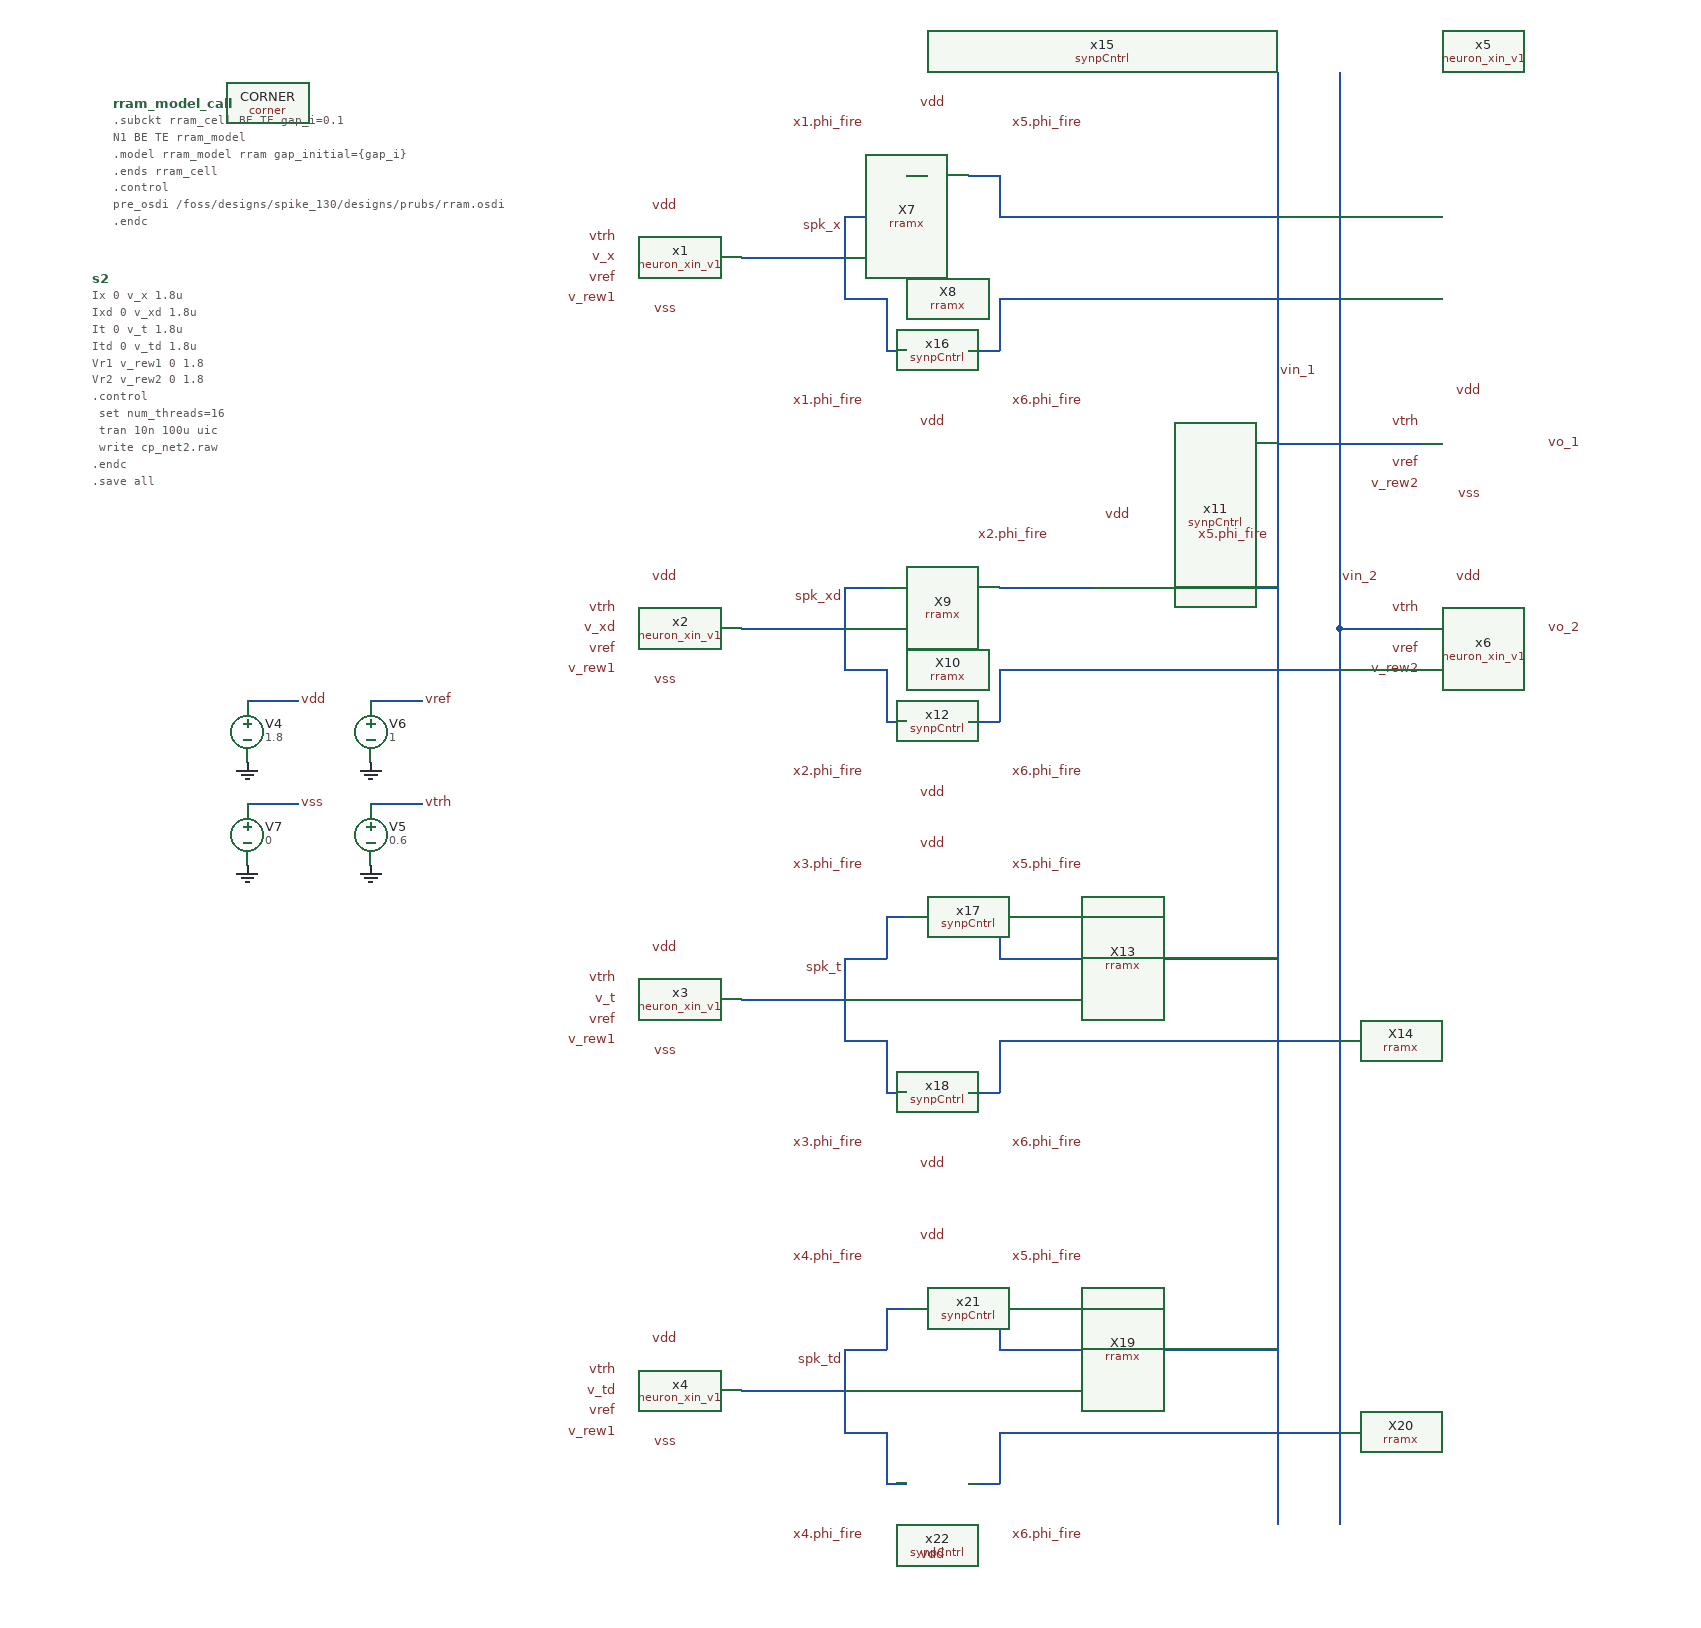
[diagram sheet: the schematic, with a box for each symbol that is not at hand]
v {xschem version=3.4.7 file_version=1.2}
G {}
K {}
V {}
S {}
E {}
B 2 540 -1630 1340 -1230 {flags=graph
y1=0.804
y2=1.924
ypos1=0
ypos2=2
divy=5
subdivy=1
unity=1
x1=-1.4999885e-05
x2=8.5000015e-05
divx=5
subdivx=1
xlabmag=1.0
ylabmag=1.0
node="v_x
v_xd
v_t
v_td"
color="4 13 6 12"
dataset=-1
unitx=1
logx=0
logy=0
}
B 2 1640 -850 2440 -450 {flags=graph
y1=0.63
y2=1.7
ypos1=0
ypos2=2
divy=5
subdivy=1
unity=1
x1=-1.4999885e-05
x2=8.5000015e-05
divx=5
subdivx=1
xlabmag=1.0
ylabmag=1.0
dataset=-1
unitx=1
logx=0
logy=0
color=6
node=spk_t}
B 2 1640 -450 2440 -50 {flags=graph
y1=0.63
y2=1.7
ypos1=0
ypos2=2
divy=5
subdivy=1
unity=1
x1=-1.4999885e-05
x2=8.5000015e-05
divx=5
subdivx=1
xlabmag=1.0
ylabmag=1.0
dataset=-1
unitx=1
logx=0
logy=0
color=12
node=spk_td}
B 2 1640 -1650 2440 -1250 {flags=graph
y1=0.63
y2=1.7
ypos1=0
ypos2=2
divy=5
subdivy=1
unity=1
x1=-1.4999885e-05
x2=8.5000015e-05
divx=5
subdivx=1
xlabmag=1.0
ylabmag=1.0
dataset=-1
unitx=1
logx=0
logy=0
color=4
node=spk_x}
B 2 1640 -1250 2440 -850 {flags=graph
y1=0.61
y2=1.7
ypos1=0
ypos2=2
divy=5
subdivy=1
unity=1
x1=-1.4999885e-05
x2=8.5000015e-05
divx=5
subdivx=1
xlabmag=1.0
ylabmag=1.0
dataset=-1
unitx=1
logx=0
logy=0
color=13
node=spk_xd}
B 2 2550 -1680 3350 -1280 {flags=graph
y1=0.68
y2=1.7
ypos1=0
ypos2=2
divy=5
subdivy=1
unity=1
x1=-1.4999885e-05
x2=8.5000015e-05
divx=5
subdivx=1
xlabmag=1.0
ylabmag=1.0
dataset=-1
unitx=1
logx=0
logy=0
color=5
node=vin_1}
B 2 2550 -1280 3350 -880 {flags=graph
y1=0.68
y2=1.7
ypos1=0
ypos2=2
divy=5
subdivy=1
unity=1
x1=-1.4999885e-05
x2=8.5000015e-05
divx=5
subdivx=1
xlabmag=1.0
ylabmag=1.0
dataset=-1
unitx=1
logx=0
logy=0
color=13
node=vin_2}
B 2 2550 -810 3350 -410 {flags=graph
y1=0.51
y2=1.8
ypos1=0
ypos2=2
divy=5
subdivy=1
unity=1
x1=-1.4999885e-05
x2=8.5000015e-05
divx=5
subdivx=1
xlabmag=1.0
ylabmag=1.0
dataset=-1
unitx=1
logx=0
logy=0
color=7
node=vo_1}
B 2 2550 -410 3350 -10 {flags=graph
y1=0.51
y2=1.8
ypos1=0
ypos2=2
divy=5
subdivy=1
unity=1
x1=-1.4999885e-05
x2=8.5000015e-05
divx=5
subdivx=1
xlabmag=1.0
ylabmag=1.0
dataset=-1
unitx=1
logx=0
logy=0
color=8
node=vo_2}
N 270 -480 320 -480 {
lab=vdd}
N 390 -380 440 -380 {
lab=vtrh}
N 390 -480 440 -480 {
lab=vref}
N 270 -380 320 -380 {
lab=vss}
N 1270 -730 1410 -730 {lab=vin_1}
N 1330 -550 1410 -550 {lab=vin_2}
N 750 -910 850 -910 {lab=spk_x}
N 750 -550 850 -550 {lab=spk_xd}
N 750 -190 850 -190 {lab=spk_t}
N 750 190 850 190 {lab=spk_td}
N 850 -950 850 -870 {lab=spk_x}
N 850 -870 890 -870 {lab=spk_x}
N 850 -950 890 -950 {lab=spk_x}
N 850 -590 850 -510 {lab=spk_xd}
N 850 -230 850 -150 {lab=spk_t}
N 850 150 850 230 {lab=spk_td}
N 890 -990 910 -990 {lab=spk_x}
N 890 -990 890 -950 {lab=spk_x}
N 970 -990 1000 -990 {lab=vin_1}
N 1000 -990 1000 -950 {lab=vin_1}
N 890 -820 910 -820 {lab=spk_x}
N 890 -870 890 -820 {lab=spk_x}
N 1000 -870 1000 -820 {lab=vin_2}
N 970 -820 1000 -820 {lab=vin_2}
N 850 -510 890 -510 {lab=spk_xd}
N 850 -590 890 -590 {lab=spk_xd}
N 890 -460 910 -460 {lab=spk_xd}
N 890 -510 890 -460 {lab=spk_xd}
N 1000 -510 1000 -460 {lab=vin_2}
N 970 -460 1000 -460 {lab=vin_2}
N 850 -150 890 -150 {lab=spk_t}
N 850 -230 890 -230 {lab=spk_t}
N 890 -270 910 -270 {lab=spk_t}
N 890 -270 890 -230 {lab=spk_t}
N 970 -270 1000 -270 {lab=vin_1}
N 1000 -270 1000 -230 {lab=vin_1}
N 890 -100 910 -100 {lab=spk_t}
N 890 -150 890 -100 {lab=spk_t}
N 1000 -150 1000 -100 {lab=vin_2}
N 970 -100 1000 -100 {lab=vin_2}
N 850 230 890 230 {lab=spk_td}
N 850 150 890 150 {lab=spk_td}
N 890 110 910 110 {lab=spk_td}
N 890 110 890 150 {lab=spk_td}
N 970 110 1000 110 {lab=vin_1}
N 1000 110 1000 150 {lab=vin_1}
N 890 280 910 280 {lab=spk_td}
N 890 230 890 280 {lab=spk_td}
N 1000 230 1000 280 {lab=vin_2}
N 970 280 1000 280 {lab=vin_2}
N 1270 -1090 1270 320 {lab=vin_1}
N 1330 -1090 1330 -550 {lab=vin_2}
N 1330 -550 1330 320 {lab=vin_2}
N 1000 230 1330 230 {lab=vin_2}
N 1000 150 1270 150 {lab=vin_1}
N 1000 -150 1330 -150 {lab=vin_2}
N 1000 -230 1270 -230 {lab=vin_1}
N 1000 -510 1330 -510 {lab=vin_2}
N 1000 -950 1270 -950 {lab=vin_1}
N 1000 -870 1330 -870 {lab=vin_2}
N 1000 -590 1090 -590 {lab=#net1}
N 1150 -590 1270 -590 {lab=vin_1}
C {devices/code_shown.sym} 120 -890 0 0 {name=s2 only_toplevel=false value="
Ix 0 v_x 1.8u
Ixd 0 v_xd 1.8u
It 0 v_t 1.8u
Itd 0 v_td 1.8u
Vr1 v_rew1 0 1.8
Vr2 v_rew2 0 1.8
.control
 set num_threads=16
 tran 10n 100u uic
 write cp_net2.raw
.endc
.save all
" }
C {devices/vsource.sym} 270 -450 0 0 {name=V4 value=1.8}
C {devices/gnd.sym} 270 -420 0 0 {name=l9 lab=GND}
C {devices/lab_wire.sym} 320 -480 0 1 {name=p61 sig_type=std_logic lab=vdd}
C {devices/vsource.sym} 390 -350 0 0 {name=V5 value=0.6}
C {devices/gnd.sym} 390 -320 0 0 {name=l10 lab=GND}
C {devices/lab_wire.sym} 440 -380 0 1 {name=p63 sig_type=std_logic lab=vtrh}
C {devices/vsource.sym} 390 -450 0 0 {name=V6 value=1}
C {devices/gnd.sym} 390 -420 0 0 {name=l11 lab=GND}
C {devices/lab_wire.sym} 440 -480 0 1 {name=p64 sig_type=std_logic lab=vref}
C {devices/vsource.sym} 270 -350 0 0 {name=V7 value=0}
C {devices/gnd.sym} 270 -320 0 0 {name=l13 lab=GND}
C {devices/lab_wire.sym} 320 -380 0 1 {name=p72 sig_type=std_logic lab=vss}
C {sky130_fd_pr/corner.sym} 290 -1060 0 0 {name=CORNER only_toplevel=true corner=tt}
C {devices/lab_wire.sym} 630 -890 0 0 {name=p2 sig_type=std_logic lab=vref}
C {devices/lab_wire.sym} 690 -960 0 0 {name=p3 sig_type=std_logic lab=vdd}
C {devices/lab_wire.sym} 630 -930 0 0 {name=p10 sig_type=std_logic lab=vtrh}
C {devices/lab_wire.sym} 690 -860 2 1 {name=p11 sig_type=std_logic lab=vss}
C {devices/lab_wire.sym} 630 -870 0 0 {name=p12 sig_type=std_logic lab=v_rew1}
C {/foss/designs/spike_130/designs/core_xin_neuron_v1/neuron_xin_v1.sym} 690 -910 0 0 {name=x1}
C {devices/lab_wire.sym} 630 -530 0 0 {name=p4 sig_type=std_logic lab=vref}
C {devices/lab_wire.sym} 690 -600 0 0 {name=p6 sig_type=std_logic lab=vdd}
C {devices/lab_wire.sym} 630 -570 0 0 {name=p13 sig_type=std_logic lab=vtrh}
C {devices/lab_wire.sym} 690 -500 2 1 {name=p14 sig_type=std_logic lab=vss}
C {devices/lab_wire.sym} 630 -510 0 0 {name=p15 sig_type=std_logic lab=v_rew1}
C {/foss/designs/spike_130/designs/core_xin_neuron_v1/neuron_xin_v1.sym} 690 -550 0 0 {name=x2}
C {devices/lab_wire.sym} 630 -170 0 0 {name=p16 sig_type=std_logic lab=vref}
C {devices/lab_wire.sym} 690 -240 0 0 {name=p17 sig_type=std_logic lab=vdd}
C {devices/lab_wire.sym} 630 -210 0 0 {name=p18 sig_type=std_logic lab=vtrh}
C {devices/lab_wire.sym} 690 -140 2 1 {name=p19 sig_type=std_logic lab=vss}
C {devices/lab_wire.sym} 630 -150 0 0 {name=p20 sig_type=std_logic lab=v_rew1}
C {/foss/designs/spike_130/designs/core_xin_neuron_v1/neuron_xin_v1.sym} 690 -190 0 0 {name=x3}
C {devices/lab_wire.sym} 630 210 0 0 {name=p21 sig_type=std_logic lab=vref}
C {devices/lab_wire.sym} 690 140 0 0 {name=p22 sig_type=std_logic lab=vdd}
C {devices/lab_wire.sym} 630 170 0 0 {name=p23 sig_type=std_logic lab=vtrh}
C {devices/lab_wire.sym} 690 240 2 1 {name=p24 sig_type=std_logic lab=vss}
C {devices/lab_wire.sym} 630 230 0 0 {name=p25 sig_type=std_logic lab=v_rew1}
C {/foss/designs/spike_130/designs/core_xin_neuron_v1/neuron_xin_v1.sym} 690 190 0 0 {name=x4}
C {devices/lab_wire.sym} 1410 -710 0 0 {name=p26 sig_type=std_logic lab=vref}
C {devices/lab_wire.sym} 1470 -780 0 0 {name=p27 sig_type=std_logic lab=vdd}
C {devices/lab_wire.sym} 1410 -750 0 0 {name=p28 sig_type=std_logic lab=vtrh}
C {devices/lab_wire.sym} 1470 -680 2 1 {name=p30 sig_type=std_logic lab=vss}
C {devices/lab_wire.sym} 1410 -690 0 0 {name=p31 sig_type=std_logic lab=v_rew2}
C {/foss/designs/spike_130/designs/core_xin_neuron_v1/neuron_xin_v1.sym} 1470 -730 0 0 {name=x5}
C {devices/lab_wire.sym} 1410 -530 0 0 {name=p32 sig_type=std_logic lab=vref}
C {devices/lab_wire.sym} 1470 -600 0 0 {name=p33 sig_type=std_logic lab=vdd}
C {devices/lab_wire.sym} 1410 -570 0 0 {name=p34 sig_type=std_logic lab=vtrh}
C {devices/lab_wire.sym} 1470 -500 2 1 {name=p35 sig_type=std_logic lab=vss}
C {devices/lab_wire.sym} 1410 -510 0 0 {name=p36 sig_type=std_logic lab=v_rew2}
C {/foss/designs/spike_130/designs/core_xin_neuron_v1/neuron_xin_v1.sym} 1470 -550 0 0 {name=x6}
C {devices/lab_wire.sym} 630 -910 0 0 {name=p1 sig_type=std_logic lab=v_x}
C {devices/lab_wire.sym} 630 -550 0 0 {name=p7 sig_type=std_logic lab=v_xd}
C {devices/lab_wire.sym} 630 -190 0 0 {name=p8 sig_type=std_logic lab=v_t}
C {devices/lab_wire.sym} 630 190 0 0 {name=p9 sig_type=std_logic lab=v_td}
C {devices/lab_wire.sym} 850 -940 0 0 {name=p37 sig_type=std_logic lab=spk_x}
C {devices/lab_wire.sym} 850 -580 0 0 {name=p38 sig_type=std_logic lab=spk_xd}
C {devices/lab_wire.sym} 850 -220 0 0 {name=p39 sig_type=std_logic lab=spk_t}
C {devices/lab_wire.sym} 850 160 0 0 {name=p40 sig_type=std_logic lab=spk_td}
C {devices/lab_wire.sym} 1530 -730 0 1 {name=p41 sig_type=std_logic lab=vo_1}
C {devices/lab_wire.sym} 1530 -550 0 1 {name=p42 sig_type=std_logic lab=vo_2}
C {devices/lab_wire.sym} 1270 -800 0 1 {name=p47 sig_type=std_logic lab=vin_1}
C {devices/lab_wire.sym} 1330 -600 0 1 {name=p48 sig_type=std_logic lab=vin_2}
C {/foss/designs/spike_130/designs/memristors/rram_v1/rramx.sym} 950 -950 0 0 {name=X7
model=rram_cell
spiceprefix=X
gap_i=0.5
}
C {/foss/designs/spike_130/designs/memristors/rram_v1/rramx.sym} 950 -870 0 0 {name=X8
model=rram_cell
spiceprefix=X
gap_i=0.5
}
C {code.sym} 140 -1060 0 0 {name=rram_model_call only_toplevel=false value=".subckt rram_cell BE TE gap_i=0.1
N1 BE TE rram_model
.model rram_model rram gap_initial=\{gap_i\}
.ends rram_cell

.control
pre_osdi /foss/designs/spike_130/designs/prubs/rram.osdi
.endc"}
C {/foss/designs/spike_130/designs/subcells/core_synpCntrl/synpCntrl.sym} 940 -1030 0 0 {name=x15}
C {devices/lab_wire.sym} 870 -1040 0 0 {name=p5 sig_type=std_logic lab=x1.phi_fire}
C {devices/lab_wire.sym} 1010 -1040 0 1 {name=p29 sig_type=std_logic lab=x5.phi_fire}
C {devices/lab_wire.sym} 920 -1060 0 1 {name=p43 sig_type=std_logic lab=vdd}
C {/foss/designs/spike_130/designs/subcells/core_synpCntrl/synpCntrl.sym} 940 -780 2 1 {name=x16}
C {devices/lab_wire.sym} 870 -770 2 1 {name=p44 sig_type=std_logic lab=x1.phi_fire}
C {devices/lab_wire.sym} 1010 -770 2 0 {name=p45 sig_type=std_logic lab=x6.phi_fire}
C {devices/lab_wire.sym} 920 -750 2 0 {name=p46 sig_type=std_logic lab=vdd}
C {/foss/designs/spike_130/designs/memristors/rram_v1/rramx.sym} 950 -590 0 0 {name=X9
model=rram_cell
spiceprefix=X
gap_i=0.5
}
C {/foss/designs/spike_130/designs/memristors/rram_v1/rramx.sym} 950 -510 0 0 {name=X10
model=rram_cell
spiceprefix=X
gap_i=0.5
}
C {/foss/designs/spike_130/designs/subcells/core_synpCntrl/synpCntrl.sym} 1120 -630 0 0 {name=x11}
C {devices/lab_wire.sym} 1050 -640 0 0 {name=p49 sig_type=std_logic lab=x2.phi_fire}
C {devices/lab_wire.sym} 1190 -640 0 1 {name=p50 sig_type=std_logic lab=x5.phi_fire}
C {devices/lab_wire.sym} 1100 -660 0 1 {name=p51 sig_type=std_logic lab=vdd}
C {/foss/designs/spike_130/designs/subcells/core_synpCntrl/synpCntrl.sym} 940 -420 2 1 {name=x12}
C {devices/lab_wire.sym} 870 -410 2 1 {name=p52 sig_type=std_logic lab=x2.phi_fire}
C {devices/lab_wire.sym} 1010 -410 2 0 {name=p53 sig_type=std_logic lab=x6.phi_fire}
C {devices/lab_wire.sym} 920 -390 2 0 {name=p54 sig_type=std_logic lab=vdd}
C {/foss/designs/spike_130/designs/memristors/rram_v1/rramx.sym} 950 -230 0 0 {name=X13
model=rram_cell
spiceprefix=X
gap_i=0.5
}
C {/foss/designs/spike_130/designs/memristors/rram_v1/rramx.sym} 950 -150 0 0 {name=X14
model=rram_cell
spiceprefix=X
gap_i=0.5
}
C {/foss/designs/spike_130/designs/subcells/core_synpCntrl/synpCntrl.sym} 940 -310 0 0 {name=x17}
C {devices/lab_wire.sym} 870 -320 0 0 {name=p55 sig_type=std_logic lab=x3.phi_fire}
C {devices/lab_wire.sym} 1010 -320 0 1 {name=p56 sig_type=std_logic lab=x5.phi_fire}
C {devices/lab_wire.sym} 920 -340 0 1 {name=p57 sig_type=std_logic lab=vdd}
C {/foss/designs/spike_130/designs/subcells/core_synpCntrl/synpCntrl.sym} 940 -60 2 1 {name=x18}
C {devices/lab_wire.sym} 870 -50 2 1 {name=p58 sig_type=std_logic lab=x3.phi_fire}
C {devices/lab_wire.sym} 1010 -50 2 0 {name=p59 sig_type=std_logic lab=x6.phi_fire}
C {devices/lab_wire.sym} 920 -30 2 0 {name=p60 sig_type=std_logic lab=vdd}
C {/foss/designs/spike_130/designs/memristors/rram_v1/rramx.sym} 950 150 0 0 {name=X19
model=rram_cell
spiceprefix=X
gap_i=0.5
}
C {/foss/designs/spike_130/designs/memristors/rram_v1/rramx.sym} 950 230 0 0 {name=X20
model=rram_cell
spiceprefix=X
gap_i=0.5
}
C {/foss/designs/spike_130/designs/subcells/core_synpCntrl/synpCntrl.sym} 940 70 0 0 {name=x21}
C {devices/lab_wire.sym} 870 60 0 0 {name=p62 sig_type=std_logic lab=x4.phi_fire}
C {devices/lab_wire.sym} 1010 60 0 1 {name=p65 sig_type=std_logic lab=x5.phi_fire}
C {devices/lab_wire.sym} 920 40 0 1 {name=p66 sig_type=std_logic lab=vdd}
C {/foss/designs/spike_130/designs/subcells/core_synpCntrl/synpCntrl.sym} 940 320 2 1 {name=x22}
C {devices/lab_wire.sym} 870 330 2 1 {name=p67 sig_type=std_logic lab=x4.phi_fire}
C {devices/lab_wire.sym} 1010 330 2 0 {name=p68 sig_type=std_logic lab=x6.phi_fire}
C {devices/lab_wire.sym} 920 350 2 0 {name=p69 sig_type=std_logic lab=vdd}
